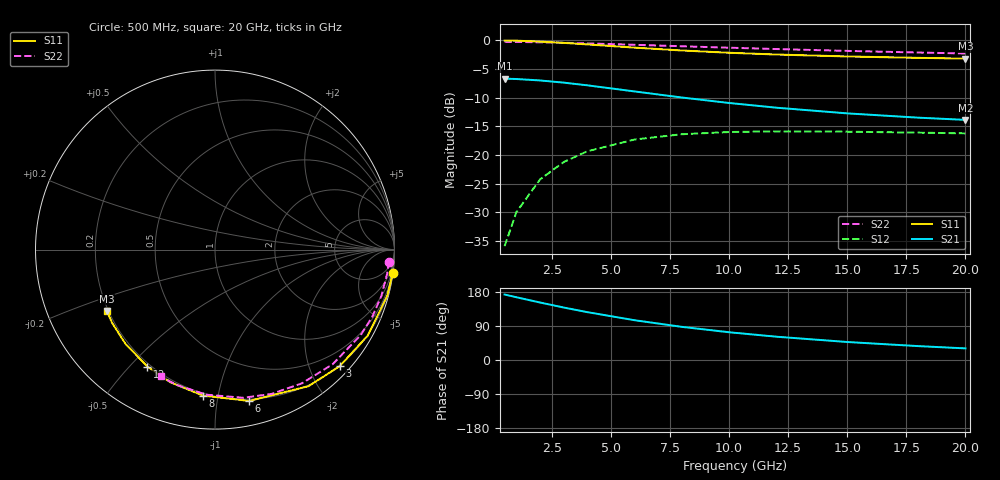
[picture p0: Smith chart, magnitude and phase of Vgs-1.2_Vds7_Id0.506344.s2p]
# Hz S RI R 50
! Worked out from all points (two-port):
!   12 points, 500 MHz to 20 GHz, reference 50 ohm
!   highest |S21| = -6.67 dB at 500 MHz (marker M1); lowest = -13.9 dB at 20 GHz (marker M2)
!   |S21| within 3 dB of the highest: start of sweep to 7.449 GHz
!   lowest |S11| = -3.2 dB at 20 GHz (marker M3), VSWR 5.53, Z = 9.65 - j12.7 ohm
!   |S11| at or under -10 dB: nowhere
!   |S22| runs from -2.3 to -0.3 dB; largest |S21 - S12| = 0.46
!   S11 on the Smith chart (normalised r, x): 500 MHz: 0, -15; 3 GHz: 0.18, -2.52; 6 GHz: 0.19, -1.23; 8 GHz: 0.19, -0.90; 12 GHz: 0.19, -0.56; 20 GHz: 0.19, -0.25
5e8  0.9899 -0.1305  -0.4602 0.0582  0.00152 0.016  0.9681 -0.0666
1e9  0.9601 -0.2565  -0.4459 0.1142  0.00598 0.0312  0.9596 -0.1324
2e9  0.8503 -0.4799  -0.3938 0.2121  0.0223 0.0571  0.9268 -0.2588
3e9  0.6949 -0.6495  -0.3207 0.2836  0.0448 0.0744  0.8761 -0.3745
4e9  0.5205 -0.7612  -0.2399 0.3268  0.0692 0.0827  0.8112 -0.4771
6e9  0.1905 -0.8431  -0.0927 0.3466  0.1118 0.0785  0.6554 -0.6386
8e9  -0.0666 -0.8136  0.0139 0.3172  0.1394 0.0603  0.4841 -0.7452
1e10  -0.2495 -0.7388  0.0821 0.2724  0.1539 0.0392  0.3146 -0.8041
1.2e10  -0.3769 -0.6515  0.1235 0.2274  0.1597 0.0201  0.1566 -0.8256
1.5e10  -0.4999 -0.5237  0.156 0.1702  0.1598 -0.00243  -0.049 -0.8082
1.8e10  -0.5725 -0.4097  0.17 0.1265  0.1557 -0.0185  -0.2137 -0.754
2e10  -0.6035 -0.3418  0.1743 0.1034  0.1523 -0.0265  -0.3027 -0.7064
